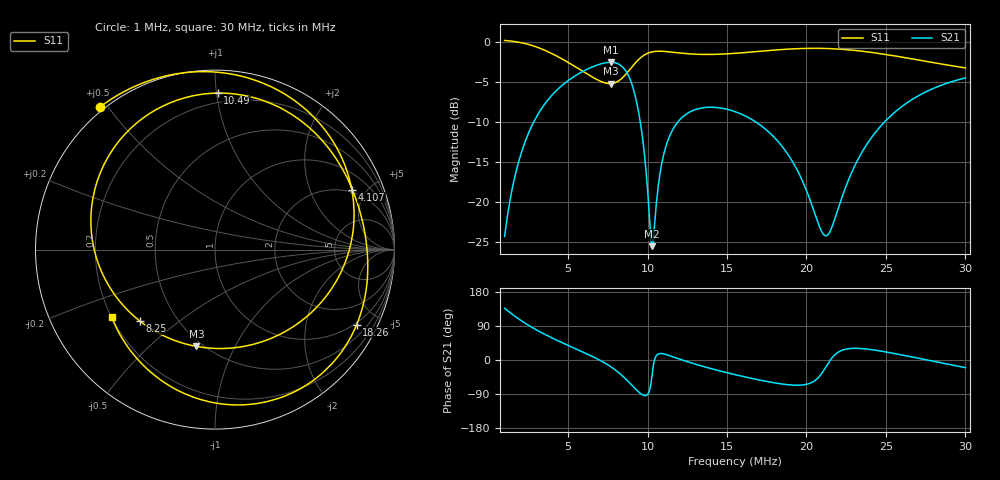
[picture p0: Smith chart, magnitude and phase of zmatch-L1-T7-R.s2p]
# HZ S RI R 50
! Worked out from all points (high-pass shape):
!   505 points, 1 MHz to 30 MHz, reference 50 ohm
!   highest |S21| = -2.55 dB at 7.675 MHz (marker M1); lowest = -25.5 dB at 10.26 MHz (marker M2)
!   |S21| within 3 dB of the highest: 4.547 MHz to 9.053 MHz (4.507 MHz wide, 66.3 % of centre); 28.3 MHz to end of sweep
!   lowest |S11| = -5.2 dB at 7.675 MHz (marker M3), VSWR 3.44, Z = 23.1 - j35.7 ohm
!   |S11| at or under -10 dB: nowhere
!   S12 and S22 are empty: the file has one direction only
!   S11 on the Smith chart (normalised r, x): 1 MHz: -0.01, +0.48; 4.107 MHz: 1.82, +3.97; 8.25 MHz: 0.31, -0.37; 10.49 MHz: 0.14, +1.01; 18.26 MHz: 0.92, -3.81; 30 MHz: 0.20, -0.29
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1000000  -0.6414 0.7936  -0.0445 0.042  0 0  0 0
1690480  -0.2095 0.9803  -0.0617 0.1376  0 0  0 0
2323420  0.1803 0.9574  -0.0265 0.2417  0 0  0 0
3244060  0.5943 0.6896  0.1032 0.3583  0 0  0 0
4107160  0.7621 0.3344  0.2697 0.3968  0 0  0 0
5833360  0.5984 -0.2857  0.5951 0.2537  0 0  0 0
7674640  -0.104 -0.5391  0.7112 -0.2247  0 0  0 0
8250040  -0.4196 -0.3973  0.5837 -0.4217  0 0  0 0
9228220  -0.6797 0.2898  0.1096 -0.4434  0 0  0 0
9746080  -0.4725 0.6732  -0.0121 -0.2224  0 0  0 0
1.026394e7  -0.1328 0.8547  0.0378 -0.0374  0 0  0 0
1.04941e7  0.0144 0.872  0.0841 0.0106  0 0  0 0
1.066672e7  0.1154 0.8664  0.1207 0.0339  0 0  0 0
1.124212e7  0.3814 0.7804  0.2309 0.0552  0 0  0 0
1.210522e7  0.6129 0.5899  0.3331 0.00598  0 0  0 0
1.550008e7  0.8479 -0.00824  0.287 -0.229  0 0  0 0
1.8262e7  0.7893 -0.4182  0.1102 -0.2084  0 0  0 0
2.033344e7  0.5989 -0.6873  0.0491 -0.0827  0 0  0 0
2.136916e7  0.4584 -0.7842  0.0624 -0.00898  0 0  0 0
2.321044e7  0.1699 -0.8642  0.1568 0.0934  0 0  0 0
2.51668e7  -0.1294 -0.8187  0.3155 0.1147  0 0  0 0
3.000016e7  -0.5756 -0.3776  0.5591 -0.2053  0 0  0 0
